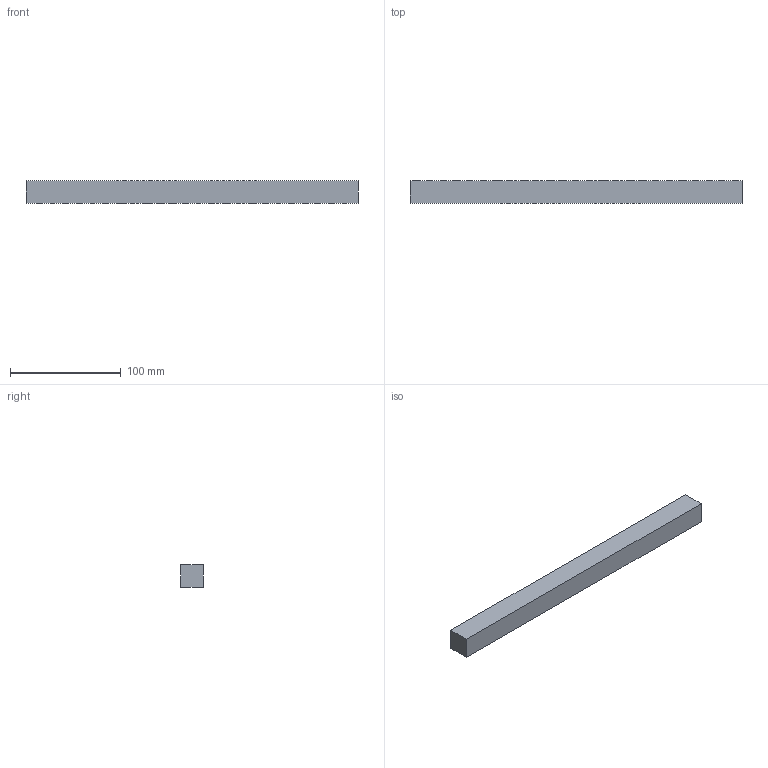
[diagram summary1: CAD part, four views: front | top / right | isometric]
IGES file: header records copied from the file, then geometry measured from it (millimetres).
Start section: START RECORD GO HERE.
Global section: file name: G40520300.igs; native system: DASSAULT SYSTEMES CATIA V5 R20 - www.3ds.com; preprocessor: CATIA Version 5 Release 20 ; author: r.borello; organization: CFTORINO; date: 20190624.150041; units: millimetre
Bounding box: 300 x 20 x 20 mm (x, y, z)
Surface area: 33153.6 mm2 (no closed solid volume)
Topology: 0 solids, 0 shells, 992 faces, 4264 edges, 3768 vertices
Faces by surface type: revolution 888, plane 104
